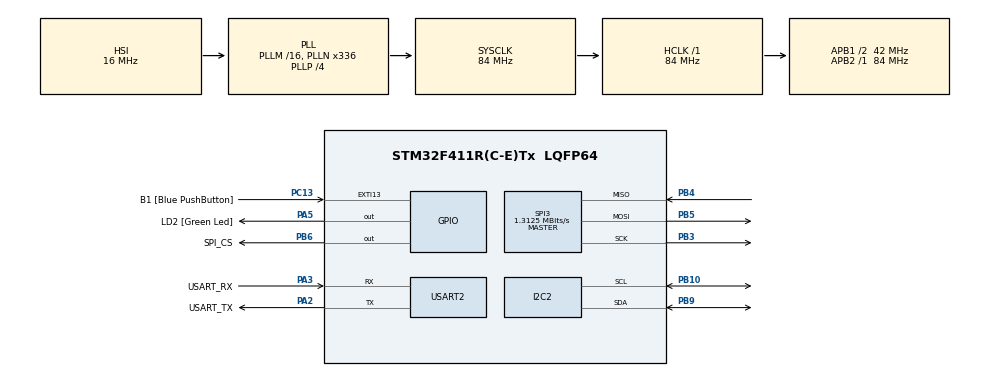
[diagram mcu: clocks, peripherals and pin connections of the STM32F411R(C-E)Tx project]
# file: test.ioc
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I2C2.I2C_Mode=I2C_Fast
Mcu.Family=STM32F4
Mcu.Name=STM32F411R(C-E)Tx
Mcu.Package=LQFP64
NVIC.PriorityGroup=NVIC_PRIORITYGROUP_0
NVIC.USART2_IRQn=true\:0\:0\:false\:false\:true\:true\:true
PA13.GPIO_Label=TMS
PA13.Mode=Serial_Wire
PA13.Signal=SYS_JTMS-SWDIO
PA14.GPIO_Label=TCK
PA14.Mode=Serial_Wire
PA14.Signal=SYS_JTCK-SWCLK
PA2.GPIO_Label=USART_TX
PA2.Mode=Asynchronous
PA2.Signal=USART2_TX
PA3.GPIO_Label=USART_RX
PA3.Mode=Asynchronous
PA3.Signal=USART2_RX
PA5.GPIO_Label=LD2 [Green Led]
PA5.Signal=GPIO_Output
PB10.Mode=I2C
PB10.Signal=I2C2_SCL
PB3.Mode=Full_Duplex_Master
PB3.Signal=SPI3_SCK
PB4.Mode=Full_Duplex_Master
PB4.Signal=SPI3_MISO
PB5.Mode=Full_Duplex_Master
PB5.Signal=SPI3_MOSI
PB6.GPIO_Label=SPI_CS
PB6.Signal=GPIO_Output
PB9.Mode=I2C
PB9.Signal=I2C2_SDA
PC13-ANTI_TAMP.GPIO_Label=B1 [Blue PushButton]
PC13-ANTI_TAMP.GPIO_ModeDefaultEXTI=GPIO_MODE_IT_FALLING
PC13-ANTI_TAMP.Signal=GPXTI13
PC14-OSC32_IN.Mode=LSE-External-Oscillator
PC14-OSC32_IN.Signal=RCC_OSC32_IN
PC15-OSC32_OUT.Mode=LSE-External-Oscillator
PC15-OSC32_OUT.Signal=RCC_OSC32_OUT
PH0\ -\ OSC_IN.Mode=HSE-External-Clock-Source
PH0\ -\ OSC_IN.Signal=RCC_OSC_IN
PH1\ -\ OSC_OUT.Mode=HSE-External-Clock-Source
PH1\ -\ OSC_OUT.Signal=RCC_OSC_OUT
ProjectManager.HeapSize=0x200
ProjectManager.StackSize=0x400
ProjectManager.TargetToolchain=SW4STM32
RCC.48MHZClocksFreq_Value=84000000
RCC.AHBFreq_Value=84000000
RCC.APB1CLKDivider=RCC_HCLK_DIV2
RCC.APB1Freq_Value=42000000
RCC.APB1TimFreq_Value=84000000
RCC.APB2Freq_Value=84000000
RCC.APB2TimFreq_Value=84000000
RCC.CortexFreq_Value=84000000
RCC.FLatency-AdvancedSettings=FLASH_LATENCY_2
RCC.HCLKFreq_Value=84000000
RCC.HSE_VALUE=8000000
RCC.HSI_VALUE=16000000
RCC.PLLN=336
RCC.PLLP=RCC_PLLP_DIV4
RCC.SYSCLKFreq_VALUE=84000000
RCC.SYSCLKSource=RCC_SYSCLKSOURCE_PLLCLK
RCC.VCOOutputFreq_Value=336000000
SPI3.BaudRatePrescaler=SPI_BAUDRATEPRESCALER_32
SPI3.CLKPhase=SPI_PHASE_2EDGE
SPI3.CLKPolarity=SPI_POLARITY_HIGH
SPI3.CalculateBaudRate=1.3125 MBits/s
SPI3.DataSize=SPI_DATASIZE_8BIT
SPI3.Direction=SPI_DIRECTION_2LINES
SPI3.Mode=SPI_MODE_MASTER
SPI3.VirtualType=VM_MASTER
USART2.VirtualMode=VM_ASYNC
board=NUCLEO-F411RE

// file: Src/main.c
/* USER CODE BEGIN Header */
/**
  ******************************************************************************
  * @file           : main.c
  * @brief          : Main program body
  ******************************************************************************
  * @attention
  *
  * <h2><center>&copy; Copyright (c) 2019 STMicroelectronics.
  * All rights reserved.</center></h2>
  *
  * This software component is licensed by ST under BSD 3-Clause license,
  * the "License"; You may not use this file except in compliance with the
  * License. You may obtain a copy of the License at:
  *                        opensource.org/licenses/BSD-3-Clause
  *
  ******************************************************************************
  */
/* USER CODE END Header */

#include "main.h"
#include <stdbool.h>
#include <stdlib.h>
#include <time.h>
/* USER CODE BEGIN Includes */
#include "ssd1306.h"
/* USER CODE END Includes */

I2C_HandleTypeDef hi2c2;

SPI_HandleTypeDef hspi3;

UART_HandleTypeDef huart2;
/* USER CODE BEGIN PV */
uint8_t data_rec[6];
int16_t x,y,z;

volatile uint8_t strUpdated = 0;
uint8_t check;
uint16_t ochar[16] = {0};
uint16_t Nchar[16] = {0};
uint16_t Ochar[16] = {0};
uint16_t Bchar[16] = {0};
uint16_t star[16] = {0};
uint16_t borden[16] = {0};

/* USER CODE END PV */

void SystemClock_Config(void);
static void MX_GPIO_Init(void);
static void MX_I2C2_Init(void);
static void MX_SPI3_Init(void);
static void MX_USART2_UART_Init(void);

/* USER CODE BEGIN 0 */
void adx1_write(uint8_t address, uint8_t value)
{
	uint8_t data[2];
	data[0] = address|0x40;
	data[1] = value;
	HAL_GPIO_WritePin(GPIOB,GPIO_PIN_6,GPIO_PIN_RESET);
	HAL_SPI_Transmit(&hspi3,data,2,100);
	HAL_GPIO_WritePin(GPIOB,GPIO_PIN_6,GPIO_PIN_SET);
}
void adx1_read(uint8_t address)
{
	address |= 0x80;
	address |= 0x40;
	uint8_t rec = 0;
	HAL_GPIO_WritePin(GPIOB,GPIO_PIN_6,GPIO_PIN_RESET);
	HAL_SPI_Transmit(&hspi3,&address,1,100);
	HAL_SPI_Receive(&hspi3,data_rec,6,100);
	HAL_GPIO_WritePin(GPIOB,GPIO_PIN_6,GPIO_PIN_SET);
}
uint8_t adx1_read_devid(void)
{
	uint8_t address = 0x00 |0x80;
	uint8_t value = 0;
	HAL_GPIO_WritePin(GPIOB,GPIO_PIN_6,GPIO_PIN_RESET);
	HAL_SPI_Transmit(&hspi3,&address,1,100);
	HAL_SPI_Receive(&hspi3,&value,1,100);
	HAL_GPIO_WritePin(GPIOB,GPIO_PIN_6,GPIO_PIN_SET);
	return value;
}
void adx1_init(void)
{
	adx1_write(0x31,0x01);
	adx1_write(0x2d,0x00);
	adx1_write(0x2d,0x08);
}
/* USER CODE END 0 */

int baitX = 100;
int baitY = 32;
int main(void)
{
	srand(100);

  /* MCU Configuration--------------------------------------------------------*/

  /* Reset of all peripherals, Initializes the Flash interface and the Systick. */
  HAL_Init();

  /* Configure the system clock */
  SystemClock_Config();

  /* Initialize all configured peripherals */
  MX_GPIO_Init();
  MX_I2C2_Init();
  MX_SPI3_Init();
  MX_USART2_UART_Init();
  /* USER CODE BEGIN 2 */
  uint8_t devid = adx1_read_devid();
  adx1_init();
  HAL_Delay(500);
  check = SSD1306_Init();
  int states[] = {0x000F, 0x0006, 0x000B, 0x000F, 0x0006, 0x000D, 0x000D, 0x0007, 0x000F, 0x000F};
    uint8_t i = 0;
  /* USER CODE END 2 */

  /* Infinite loop */
  /* USER CODE BEGIN WHILE */
  int speed = 1;
  uint8_t level = 1;
   uint8_t outputStr[80] = {0};
   bool gameover = false;
   int xg=64,yg=30,zg=50;
  while (1)
  {
    /* USER CODE END WHILE */
	  GPIOA->ODR = (states[level]<<4);
    /* USER CODE BEGIN 3 */
	  adx1_read(0x32);
	  	  x = ((data_rec[1] << 8) | data_rec[0]);
	  	  y = ((data_rec[3] << 8) | data_rec[2]);
	  	  z = ((data_rec[5] << 8) | data_rec[4]);
	  	strUpdated = 1;

	  	if(x<0){
	  		xg+=speed;
	  	}
	  	else{
	  		xg-=speed;
	  	}
	  	if(y<0){
	  		yg-=speed;
	  	}
	  	else{
	  		yg+=speed;
	  	}
	  	ochar[0]='o';
	  	Nchar[0]='N';
	  	Ochar[0]='O';
	  	Bchar[0]='B';
	  	star[0] ='*';
	  	if(strUpdated){
	  		if(xg >= baitX - 2  && xg <= baitX + 2){
	  			if(yg >= baitY - 2  && yg <= baitY + 2){
	  				baitX = rand() % 124 +2;
	  				baitY = rand() % 58 +2;
	  				speed += 2;
	  				++level;
	  				SSD1306_UpdateScreen();
	  				strUpdated = 0;
	  			}
	  		}
	  		if(gameover == true)
	  		{
	  			SSD1306_Fill(SSD1306_COLOR_BLACK);
	  			SSD1306_GotoXY(24,20);
	  			SSD1306_Puts(Nchar,&Font_16x26,1);
	  			SSD1306_GotoXY(44,20);
	  			SSD1306_Puts(Ochar,&Font_16x26,1);
	  			SSD1306_GotoXY(64,20);
	  			SSD1306_Puts(Ochar,&Font_16x26,1);
	  			SSD1306_GotoXY(84,20);
	  			SSD1306_Puts(Bchar,&Font_16x26,1);
	  			SSD1306_UpdateScreen();
	  			strUpdated = 0;
	  		}
	  		else{
	  			SSD1306_Fill(SSD1306_COLOR_BLACK);
	  			SSD1306_GotoXY(xg,yg);
	  			SSD1306_Puts(ochar,&Font_7x10,1);
	  			SSD1306_GotoXY(baitX,baitY);
	  			SSD1306_Puts(star,&Font_7x10,1);
	  			SSD1306_DrawLine(1,  1,  127,  1,  1);
	  			SSD1306_DrawLine(1,  1,  1,  64,  1);
	  			SSD1306_DrawLine(127,  1,  127,  64,  1);
	  			SSD1306_DrawLine(1,  64,  127,  64,  1);
	  			SSD1306_UpdateScreen();
	  			strUpdated = 0;
	  			if(xg>=127 || xg <=1 || yg <= 1 || yg >=64){
	  				gameover = true;
	  			}
	  			HAL_Delay(100);
	  		}
	  	}

  }
  /* USER CODE END 3 */
}

void SystemClock_Config(void)
{
  RCC_OscInitTypeDef RCC_OscInitStruct = {0};
  RCC_ClkInitTypeDef RCC_ClkInitStruct = {0};

  /** Configure the main internal regulator output voltage
  */
  __HAL_RCC_PWR_CLK_ENABLE();
  __HAL_PWR_VOLTAGESCALING_CONFIG(PWR_REGULATOR_VOLTAGE_SCALE1);
  /** Initializes the CPU, AHB and APB busses clocks
  */
  RCC_OscInitStruct.OscillatorType = RCC_OSCILLATORTYPE_HSI;
  RCC_OscInitStruct.HSIState = RCC_HSI_ON;
  RCC_OscInitStruct.HSICalibrationValue = RCC_HSICALIBRATION_DEFAULT;
  RCC_OscInitStruct.PLL.PLLState = RCC_PLL_ON;
  RCC_OscInitStruct.PLL.PLLSource = RCC_PLLSOURCE_HSI;
  RCC_OscInitStruct.PLL.PLLM = 16;
  RCC_OscInitStruct.PLL.PLLN = 336;
  RCC_OscInitStruct.PLL.PLLP = RCC_PLLP_DIV4;
  RCC_OscInitStruct.PLL.PLLQ = 4;
  if (HAL_RCC_OscConfig(&RCC_OscInitStruct) != HAL_OK)
  {
    Error_Handler();
  }
  /** Initializes the CPU, AHB and APB busses clocks
  */
  RCC_ClkInitStruct.ClockType = RCC_CLOCKTYPE_HCLK|RCC_CLOCKTYPE_SYSCLK
                              |RCC_CLOCKTYPE_PCLK1|RCC_CLOCKTYPE_PCLK2;
  RCC_ClkInitStruct.SYSCLKSource = RCC_SYSCLKSOURCE_PLLCLK;
  RCC_ClkInitStruct.AHBCLKDivider = RCC_SYSCLK_DIV1;
  RCC_ClkInitStruct.APB1CLKDivider = RCC_HCLK_DIV2;
  RCC_ClkInitStruct.APB2CLKDivider = RCC_HCLK_DIV1;

  if (HAL_RCC_ClockConfig(&RCC_ClkInitStruct, FLASH_LATENCY_2) != HAL_OK)
  {
    Error_Handler();
  }
}

static void MX_I2C2_Init(void)
{

  hi2c2.Instance = I2C2;
  hi2c2.Init.ClockSpeed = 400000;
  hi2c2.Init.DutyCycle = I2C_DUTYCYCLE_2;
  hi2c2.Init.OwnAddress1 = 0;
  hi2c2.Init.AddressingMode = I2C_ADDRESSINGMODE_7BIT;
  hi2c2.Init.DualAddressMode = I2C_DUALADDRESS_DISABLE;
  hi2c2.Init.OwnAddress2 = 0;
  hi2c2.Init.GeneralCallMode = I2C_GENERALCALL_DISABLE;
  hi2c2.Init.NoStretchMode = I2C_NOSTRETCH_DISABLE;
  if (HAL_I2C_Init(&hi2c2) != HAL_OK)
  {
    Error_Handler();
  }

}

static void MX_SPI3_Init(void)
{

  /* SPI3 parameter configuration*/
  hspi3.Instance = SPI3;
  hspi3.Init.Mode = SPI_MODE_MASTER;
  hspi3.Init.Direction = SPI_DIRECTION_2LINES;
  hspi3.Init.DataSize = SPI_DATASIZE_8BIT;
  hspi3.Init.CLKPolarity = SPI_POLARITY_HIGH;
  hspi3.Init.CLKPhase = SPI_PHASE_2EDGE;
  hspi3.Init.NSS = SPI_NSS_SOFT;
  hspi3.Init.BaudRatePrescaler = SPI_BAUDRATEPRESCALER_32;
  hspi3.Init.FirstBit = SPI_FIRSTBIT_MSB;
  hspi3.Init.TIMode = SPI_TIMODE_DISABLE;
  hspi3.Init.CRCCalculation = SPI_CRCCALCULATION_DISABLE;
  hspi3.Init.CRCPolynomial = 10;
  if (HAL_SPI_Init(&hspi3) != HAL_OK)
  {
    Error_Handler();
  }

}

static void MX_USART2_UART_Init(void)
{

  huart2.Instance = USART2;
  huart2.Init.BaudRate = 115200;
  huart2.Init.WordLength = UART_WORDLENGTH_8B;
  huart2.Init.StopBits = UART_STOPBITS_1;
  huart2.Init.Parity = UART_PARITY_NONE;
  huart2.Init.Mode = UART_MODE_TX_RX;
  huart2.Init.HwFlowCtl = UART_HWCONTROL_NONE;
  huart2.Init.OverSampling = UART_OVERSAMPLING_16;
  if (HAL_UART_Init(&huart2) != HAL_OK)
  {
    Error_Handler();
  }

}

static void MX_GPIO_Init(void)
{
  GPIO_InitTypeDef GPIO_InitStruct = {0};

  /* GPIO Ports Clock Enable */
  __HAL_RCC_GPIOC_CLK_ENABLE();
  __HAL_RCC_GPIOH_CLK_ENABLE();
  __HAL_RCC_GPIOA_CLK_ENABLE();
  __HAL_RCC_GPIOB_CLK_ENABLE();

  /*Configure GPIO pin Output Level */
  HAL_GPIO_WritePin(GPIOA, SEG0_Pin|SEG1_Pin|SEG2_Pin|SEG3_Pin
                          |SEG4_Pin|SEG5_Pin|SEG6_Pin, GPIO_PIN_RESET);

  /*Configure GPIO pin Output Level */
  HAL_GPIO_WritePin(SPI_CS_GPIO_Port, SPI_CS_Pin, GPIO_PIN_RESET);

  /*Configure GPIO pin : B1_Pin */
  GPIO_InitStruct.Pin = B1_Pin;
  GPIO_InitStruct.Mode = GPIO_MODE_IT_FALLING;
  GPIO_InitStruct.Pull = GPIO_NOPULL;
  HAL_GPIO_Init(B1_GPIO_Port, &GPIO_InitStruct);

  /*Configure GPIO pins : SEG0_Pin SEG1_Pin SEG2_Pin SEG3_Pin
                           SEG4_Pin SEG6_Pin SEG7_Pin */
  GPIO_InitStruct.Pin = SEG0_Pin|SEG1_Pin|SEG2_Pin|SEG3_Pin
                          |SEG4_Pin|SEG5_Pin|SEG6_Pin;
  GPIO_InitStruct.Mode = GPIO_MODE_OUTPUT_PP;
  GPIO_InitStruct.Pull = GPIO_NOPULL;
  GPIO_InitStruct.Speed = GPIO_SPEED_FREQ_LOW;
  HAL_GPIO_Init(GPIOA, &GPIO_InitStruct);

  /*Configure GPIO pin : SPI_CS_Pin */
  GPIO_InitStruct.Pin = SPI_CS_Pin;
  GPIO_InitStruct.Mode = GPIO_MODE_OUTPUT_PP;
  GPIO_InitStruct.Pull = GPIO_NOPULL;
  GPIO_InitStruct.Speed = GPIO_SPEED_FREQ_LOW;
  HAL_GPIO_Init(SPI_CS_GPIO_Port, &GPIO_InitStruct);

}

void Error_Handler(void)
{
}

/************************ (C) COPYRIGHT STMicroelectronics *****END OF FILE****/
